One B-rep face of a CAD part: STEP entity #306.
In plain terms, the planar face has unit normal (1, 0, 0).
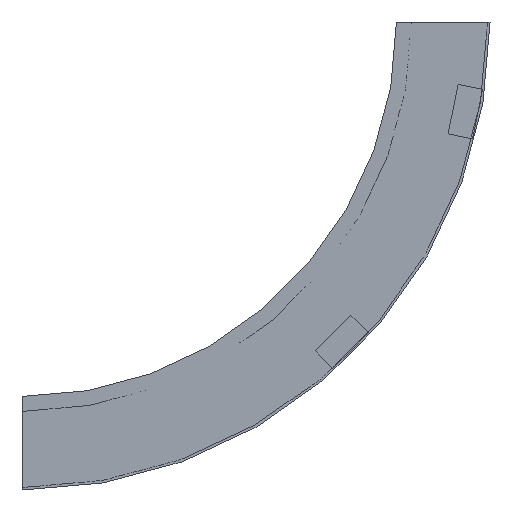
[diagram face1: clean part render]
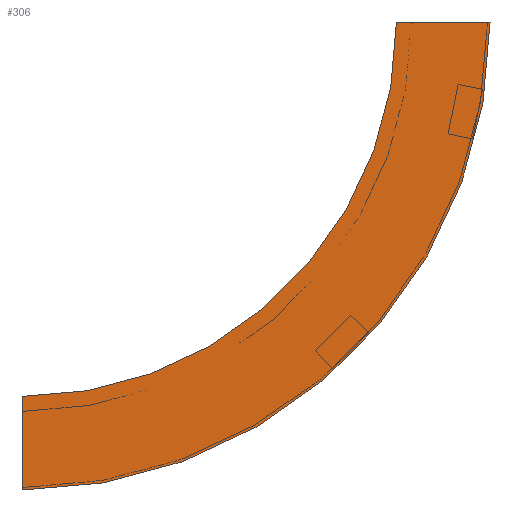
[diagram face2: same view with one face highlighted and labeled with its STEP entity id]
Its self-contained STEP definition (entity closure, numbers rounded to 3 decimals):
#23 = CARTESIAN_POINT ( 'NONE',  ( 0., 300., -375. ) ) ;
#47 = CIRCLE ( 'NONE', #160, 300. ) ;
#69 = LINE ( 'NONE', #23, #228 ) ;
#99 = CARTESIAN_POINT ( 'NONE',  ( 0., 0., 0. ) ) ;
#103 = CARTESIAN_POINT ( 'NONE',  ( 0., 300., 0. ) ) ;
#115 = ORIENTED_EDGE ( 'NONE', *, *, #243, .F. ) ;
#119 = DIRECTION ( 'NONE',  ( 0., 0., 1. ) ) ;
#120 = AXIS2_PLACEMENT_3D ( 'NONE', #103, #443, #549 ) ;
#129 = EDGE_LOOP ( 'NONE', ( #446, #115, #580, #177 ) ) ;
#131 = EDGE_CURVE ( 'NONE', #405, #145, #47, .T. ) ;
#134 = VERTEX_POINT ( 'NONE', #295 ) ;
#143 = EDGE_CURVE ( 'NONE', #380, #145, #69, .T. ) ;
#145 = VERTEX_POINT ( 'NONE', #237 ) ;
#148 = FACE_OUTER_BOUND ( 'NONE', #129, .T. ) ;
#160 = AXIS2_PLACEMENT_3D ( 'NONE', #568, #558, #471 ) ;
#169 = LINE ( 'NONE', #258, #291 ) ;
#177 = ORIENTED_EDGE ( 'NONE', *, *, #143, .T. ) ;
#228 = VECTOR ( 'NONE', #119, 1000. ) ;
#237 = CARTESIAN_POINT ( 'NONE',  ( 0., 300., -300. ) ) ;
#243 = EDGE_CURVE ( 'NONE', #134, #405, #169, .T. ) ;
#258 = CARTESIAN_POINT ( 'NONE',  ( 0., -75., 0. ) ) ;
#275 = DIRECTION ( 'NONE',  ( -1., 0., 0. ) ) ;
#291 = VECTOR ( 'NONE', #538, 1000. ) ;
#295 = CARTESIAN_POINT ( 'NONE',  ( 0., -75., 0. ) ) ;
#306 = ADVANCED_FACE ( 'NONE', ( #148 ), #317, .F. ) ;
#317 = PLANE ( 'NONE',  #341 ) ;
#321 = EDGE_CURVE ( 'NONE', #134, #380, #489, .T. ) ;
#341 = AXIS2_PLACEMENT_3D ( 'NONE', #506, #275, #499 ) ;
#380 = VERTEX_POINT ( 'NONE', #518 ) ;
#405 = VERTEX_POINT ( 'NONE', #99 ) ;
#443 = DIRECTION ( 'NONE',  ( 1., 0., 0. ) ) ;
#446 = ORIENTED_EDGE ( 'NONE', *, *, #131, .F. ) ;
#471 = DIRECTION ( 'NONE',  ( 0., -1., 0. ) ) ;
#489 = CIRCLE ( 'NONE', #120, 375. ) ;
#499 = DIRECTION ( 'NONE',  ( 0., 0., 1. ) ) ;
#506 = CARTESIAN_POINT ( 'NONE',  ( 0., -75., 0. ) ) ;
#518 = CARTESIAN_POINT ( 'NONE',  ( 0., 300., -375. ) ) ;
#538 = DIRECTION ( 'NONE',  ( 0., 1., 0. ) ) ;
#549 = DIRECTION ( 'NONE',  ( 0., -1., 0. ) ) ;
#558 = DIRECTION ( 'NONE',  ( 1., 0., 0. ) ) ;
#568 = CARTESIAN_POINT ( 'NONE',  ( 0., 300., 0. ) ) ;
#580 = ORIENTED_EDGE ( 'NONE', *, *, #321, .T. ) ;
